One B-rep face of a CAD part: STEP entity #820.
In plain terms, the cylindrical face has radius 16 mm (diameter 32 mm), a partial arc.
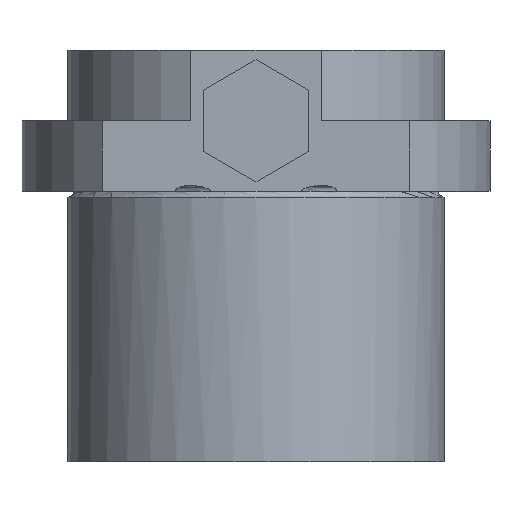
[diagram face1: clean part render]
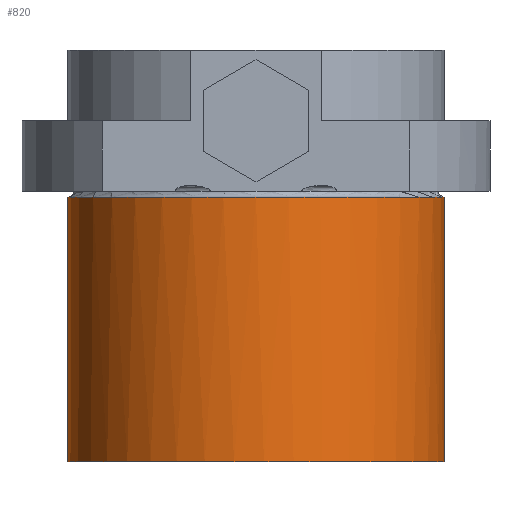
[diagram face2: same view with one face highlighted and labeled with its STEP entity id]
Its self-contained STEP definition (entity closure, numbers rounded to 3 decimals):
#452=CARTESIAN_POINT('Control Point',(-16.,0.,-23.)) ;
#453=CARTESIAN_POINT('Control Point',(-16.,-1.568,-23.)) ;
#454=CARTESIAN_POINT('Control Point',(-15.808,-3.135,-23.)) ;
#455=CARTESIAN_POINT('Control Point',(-15.424,-4.672,-23.)) ;
#456=CARTESIAN_POINT('Control Point',(-14.288,-7.619,-23.)) ;
#457=CARTESIAN_POINT('Control Point',(-12.473,-10.205,-23.)) ;
#458=CARTESIAN_POINT('Control Point',(-11.412,-11.38,-23.)) ;
#459=CARTESIAN_POINT('Control Point',(-9.022,-13.446,-23.)) ;
#460=CARTESIAN_POINT('Control Point',(-6.205,-14.874,-23.)) ;
#461=CARTESIAN_POINT('Control Point',(-4.715,-15.411,-23.)) ;
#462=CARTESIAN_POINT('Control Point',(-1.634,-16.109,-23.)) ;
#463=CARTESIAN_POINT('Control Point',(1.524,-16.044,-23.)) ;
#464=CARTESIAN_POINT('Control Point',(3.091,-15.817,-23.)) ;
#465=CARTESIAN_POINT('Control Point',(6.138,-14.984,-23.)) ;
#466=CARTESIAN_POINT('Control Point',(8.894,-13.44,-23.)) ;
#467=CARTESIAN_POINT('Control Point',(10.17,-12.502,-23.)) ;
#468=CARTESIAN_POINT('Control Point',(12.466,-10.333,-23.)) ;
#469=CARTESIAN_POINT('Control Point',(14.171,-7.674,-23.)) ;
#470=CARTESIAN_POINT('Control Point',(14.856,-6.246,-23.)) ;
#471=CARTESIAN_POINT('Control Point',(15.567,-4.131,-23.)) ;
#472=CARTESIAN_POINT('Control Point',(15.902,-1.939,-23.)) ;
#473=CARTESIAN_POINT('Control Point',(15.967,-1.294,-23.)) ;
#474=CARTESIAN_POINT('Control Point',(16.,-0.647,-23.)) ;
#475=CARTESIAN_POINT('Control Point',(16.,0.,-23.)) ;
#476=CARTESIAN_POINT('Vertex',(-16.,0.,-23.)) ;
#478=CARTESIAN_POINT('Vertex',(16.,0.,-23.)) ;
#790=CARTESIAN_POINT('Axis2P3D Location',(0.,0.,12.)) ;
#795=CARTESIAN_POINT('Line Origine',(16.,0.,12.)) ;
#799=CARTESIAN_POINT('Vertex',(16.,0.,-0.5)) ;
#802=CARTESIAN_POINT('Axis2P3D Location',(0.,0.,-0.5)) ;
#806=CARTESIAN_POINT('Vertex',(-16.,0.,-0.5)) ;
#809=CARTESIAN_POINT('Line Origine',(-16.,0.,12.)) ;
#791=DIRECTION('Axis2P3D Direction',(0.,0.,-1.)) ;
#792=DIRECTION('Axis2P3D XDirection',(1.,0.,0.)) ;
#796=DIRECTION('Vector Direction',(0.,0.,-1.)) ;
#803=DIRECTION('Axis2P3D Direction',(0.,0.,-1.)) ;
#810=DIRECTION('Vector Direction',(0.,0.,-1.)) ;
#793=AXIS2_PLACEMENT_3D('Cylinder Axis2P3D',#790,#791,#792) ;
#804=AXIS2_PLACEMENT_3D('Circle Axis2P3D',#802,#803,$) ;
#815=ORIENTED_EDGE('',*,*,#801,.T.) ;
#816=ORIENTED_EDGE('',*,*,#808,.F.) ;
#817=ORIENTED_EDGE('',*,*,#813,.T.) ;
#818=ORIENTED_EDGE('',*,*,#480,.T.) ;
#797=VECTOR('Line Direction',#796,1.) ;
#811=VECTOR('Line Direction',#810,1.) ;
#820=ADVANCED_FACE('740-19',(#819),#794,.T.) ;
#451=B_SPLINE_CURVE_WITH_KNOTS('',5,(#452,#453,#454,#455,#456,#457,#458,#459,#460,#461,#462,#463,#464,#465,#466,#467,#468,#469,#470,#471,#472,#473,#474,#475),.UNSPECIFIED.,.F.,.U.,(6,3,3,3,3,3,3,6),(0.,11.085,22.17,33.255,44.34,55.425,66.51,71.085),.UNSPECIFIED.) ;
#805=CIRCLE('generated circle',#804,16.) ;
#794=CYLINDRICAL_SURFACE('generated cylinder',#793,16.) ;
#480=EDGE_CURVE('',#477,#479,#451,.T.) ;
#801=EDGE_CURVE('',#479,#800,#798,.F.) ;
#808=EDGE_CURVE('',#807,#800,#805,.F.) ;
#813=EDGE_CURVE('',#807,#477,#812,.T.) ;
#814=EDGE_LOOP('',(#815,#816,#817,#818)) ;
#819=FACE_OUTER_BOUND('',#814,.T.) ;
#798=LINE('Line',#795,#797) ;
#812=LINE('Line',#809,#811) ;
#477=VERTEX_POINT('',#476) ;
#479=VERTEX_POINT('',#478) ;
#800=VERTEX_POINT('',#799) ;
#807=VERTEX_POINT('',#806) ;
